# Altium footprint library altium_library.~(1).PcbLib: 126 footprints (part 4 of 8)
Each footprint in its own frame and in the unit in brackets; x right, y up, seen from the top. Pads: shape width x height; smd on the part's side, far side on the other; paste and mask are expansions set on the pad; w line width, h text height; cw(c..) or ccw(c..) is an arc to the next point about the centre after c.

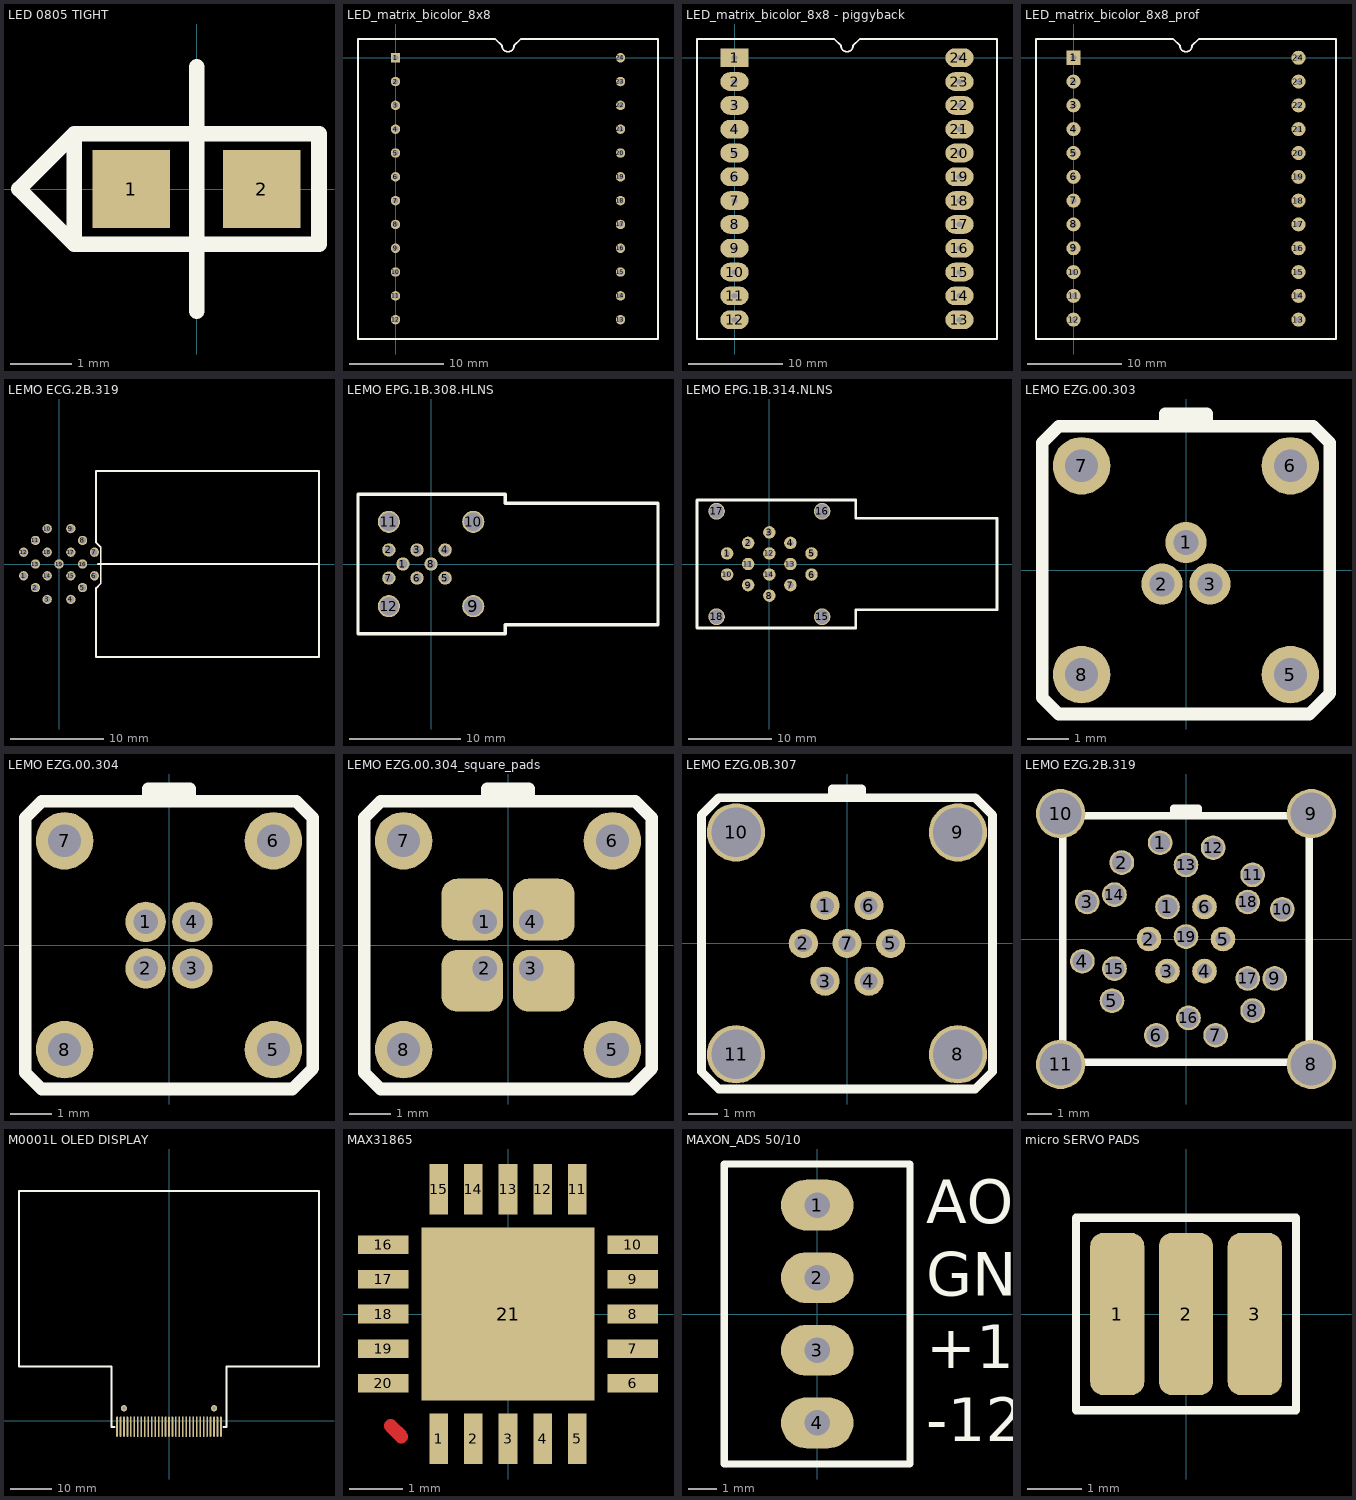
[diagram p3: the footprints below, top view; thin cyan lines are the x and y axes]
## LED 0805 TIGHT [mil]
pads (2):
  rect 50x50 smd: 1(-42,0) 2(42,0)
Top Overlay:
  lines w10: 0,-78.74 0,78.74 ; -114.17,0 -78.74,35.43 ; -114.17,0 -114.17,0 ; -114.17,0 -78.74,-35.43 ; -78.74,-35.43 -78.74,-26.74 -78.74,35.43 ; -78.74,-35.43 78.74,-35.43 78.74,35.43 -78.74,35.43

## LED_matrix_bicolor_8x8 [mm]
pads (24):
  rect 1x1 / inner rect 3x2 / far side rect 3x2 hole 0.6: 1(0,0)
  round 1 / inner oval 3x2 / far side oval 3x2 hole 0.6: 2(0,-2.54) 3(0,-5.08) 4(0,-7.62) 5(0,-10.16) 6(0,-12.7) 7(0,-15.24) 8(0,-17.78) 9(0,-20.32) 10(0,-22.86) 11(0,-25.4) 12(0,-27.94) 13(24,-27.94) 14(24,-25.4) 15(24,-22.86) 16(24,-20.32) 17(24,-17.78) 18(24,-15.24) 19(24,-12.7) 20(24,-10.16) 21(24,-7.62) 22(24,-5.08) 23(24,-2.54) 24(24,0)
Top Overlay:
  lines w0.2: -4,-30 -4,2 10.635,2 11.365,1.27 ccw(c12,1.27) 12.635,1.27 13.365,2 28,2 28,-30 -4,-30

## LED_matrix_bicolor_8x8 - piggyback [mm]
pads (24):
  rect 3x2 hole 0.6: 1(0,0)
  oval 3x2 hole 0.6: 2(0,-2.54) 3(0,-5.08) 4(0,-7.62) 5(0,-10.16) 6(0,-12.7) 7(0,-15.24) 8(0,-17.78) 9(0,-20.32) 10(0,-22.86) 11(0,-25.4) 12(0,-27.94) 13(24,-27.94) 14(24,-25.4) 15(24,-22.86) 16(24,-20.32) 17(24,-17.78) 18(24,-15.24) 19(24,-12.7) 20(24,-10.16) 21(24,-7.62) 22(24,-5.08) 23(24,-2.54) 24(24,0)
Top Overlay:
  lines w0.2: -4,-30 28,-30 28,2 13.365,2 12.635,1.27 cw(c12,1.27) 11.365,1.27 10.635,2 -4,2 -4,-30

## LED_matrix_bicolor_8x8_prof [mm] "made for proffesional pcb manuf."
height 8
pads (24):
  rect 1.5x1.5 hole 0.6: 1(0,0)
  round 1.5 hole 0.6: 2(0,-2.54) 3(0,-5.08) 4(0,-7.62) 5(0,-10.16) 6(0,-12.7) 7(0,-15.24) 8(0,-17.78) 9(0,-20.32) 10(0,-22.86) 11(0,-25.4) 12(0,-27.94) 13(24,-27.94) 14(24,-25.4) 15(24,-22.86) 16(24,-20.32) 17(24,-17.78) 18(24,-15.24) 19(24,-12.7) 20(24,-10.16) 21(24,-7.62) 22(24,-5.08) 23(24,-2.54) 24(24,0)
Top Overlay:
  lines w0.2: -4,-30 -4,2 10.635,2 11.365,1.27 ccw(c12,1.27) 12.635,1.27 13.365,2 28,2 28,-30 -4,-30

## LEMO ECG.2B.319 [mm]
pads (19):
  round 1 hole 0.7: 1(-3.81,-1.27) 2(-2.54,-2.54) 3(-1.27,-3.81) 4(1.27,-3.81) 5(2.54,-2.54) 6(3.81,-1.27) 7(3.81,1.27) 8(2.54,2.54) 9(1.27,3.81) 10(-1.27,3.81) 11(-2.54,2.54) 12(-3.81,1.27) 13(-2.54,0) 14(-1.27,-1.27) 15(1.27,-1.27) 16(2.54,0) 17(1.27,1.27) 18(-1.27,1.27) 19(0,0)
Top Overlay:
  lines w0.203: 4.2,0 28,0 ; 4.4,1.9 4,2.3 4,10 28,10 28,0 ; 4.4,1.9 4.4,1.9 ; 4.4,1.9 4.5,1.8 4.5,-2.1 4,-2.6 4,-10 28,-10 28,0

## LEMO EPG.1B.308.HLNS [mm]
height 14
pads (12):
  round 1.2 hole 0.8: 1(-2.54,0) 2(-3.81,1.27) 3(-1.27,1.27) 4(1.27,1.27) 5(1.27,-1.27) 6(-1.27,-1.27) 7(-3.81,-1.27) 8(0,0)
  round 2 / inner round 3 / far side round 3.6 hole 1.7: 9(3.81,-3.81) 10(3.81,3.81) 11(-3.81,3.81) 12(-3.81,-3.81)
Top Overlay:
  lines w0.305: -6.6,-6.3 -6.6,6.3 6.7,6.3 6.7,5.5 20.5,5.5 20.5,-5.5 6.7,-5.5 6.7,-6.3 -6.6,-6.3

## LEMO EPG.1B.314.NLNS [mm]
height 14.3
pads (18):
  round 1.5 hole 0.7: 1(-5.08,1.27) 2(-2.54,2.54) 3(0,3.81) 4(2.54,2.54) 5(5.08,1.27) 6(5.08,-1.27) 7(2.54,-2.54) 8(0,-3.81) 9(-2.54,-2.54) 10(-5.08,-1.27) 11(-2.54,0) 12(0,1.27) 13(2.54,0) 14(0,-1.27)
  round 2 / inner round 3 / far side round 4.1 hole 1.7: 15(6.35,-6.35) 16(6.35,6.35) 17(-6.35,6.35) 18(-6.35,-6.35)
Top Overlay:
  lines w0.305: -8.7,-7.7 -8.7,7.7 10.4,7.7 10.4,5.5 27.4,5.5 27.4,-5.5 10.4,-5.5 10.4,-7.7 -8.7,-7.7

## LEMO EZG.00.303 [mm]
height 15
pads (7):
  round 1 hole 0.6: 1(0,0.675) 2(-0.585,-0.337) 3(0.585,-0.337)
  round 1.4 / inner round 2 / far side round 2 hole 0.8: 5(2.54,-2.54) 6(2.54,2.54) 7(-2.54,2.54) 8(-2.54,-2.54)
Top Overlay:
  lines w0.305: -0.5,3.5 -0.5,3.8 0.5,3.8 0.5,3.5 ; 3.5,-3 3.5,3.1 3.1,3.5 -3.1,3.5 -3.5,3.1 -3.5,-3.1 -3.1,-3.5 3,-3.5 3.5,-3 ; 3.5,-3 3.5,-3

## LEMO EZG.00.304 [mm]
height 15
pads (8):
  round 0.982 hole 0.6: 1(-0.567,0.567) 2(-0.567,-0.567) 3(0.567,-0.567) 4(0.567,0.567)
  round 1.4 / inner round 2 / far side round 2 hole 0.8: 5(2.54,-2.54) 6(2.54,2.54) 7(-2.54,2.54) 8(-2.54,-2.54)
Top Overlay:
  lines w0.305: -0.5,3.5 -0.5,3.8 0.5,3.8 0.5,3.5 ; 3.5,-3 3,-3.5 -3.1,-3.5 -3.5,-3.1 -3.5,3.1 -3.1,3.5 3.1,3.5 3.5,3.1 3.5,-3 ; 3.5,-3 3.5,-3

## LEMO EZG.00.304_square_pads [mm]
height 15
pads (8):
  rrect50% 1.5x1.5 hole 0.6 copper offset -0.3,0.3: 1(-0.567,0.567)
  rrect50% 1.5x1.5 hole 0.6 copper offset -0.3,-0.3: 2(-0.567,-0.567)
  rrect50% 1.5x1.5 hole 0.6 copper offset 0.3,-0.3: 3(0.567,-0.567)
  rrect50% 1.5x1.5 hole 0.6 copper offset 0.3,0.3: 4(0.567,0.567)
  round 1.4 / inner round 2 / far side round 2 hole 0.8: 5(2.54,-2.54) 6(2.54,2.54) 7(-2.54,2.54) 8(-2.54,-2.54)
Top Overlay:
  lines w0.305: -0.5,3.5 -0.5,3.8 0.5,3.8 0.5,3.5 ; 3.5,-3 3,-3.5 -3.1,-3.5 -3.5,-3.1 -3.5,3.1 -3.1,3.5 3.1,3.5 3.5,3.1 3.5,-3 ; 3.5,-3 3.5,-3

## LEMO EZG.0B.307 [mm]
height 15
pads (11):
  round 1 hole 0.6: 1(-0.75,1.299) 2(-1.5,0) 3(-0.75,-1.299) 4(0.75,-1.299) 5(1.5,0) 6(0.75,1.299) 7(0,0)
  round 2 / inner round 3 / far side round 4.1 hole 1.7: 8(3.81,-3.81) 9(3.81,3.81) 10(-3.81,3.81) 11(-3.81,-3.81)
Top Overlay:
  lines w0.305: -0.5,5 -0.5,5.3 0.5,5.3 0.5,5 ; -5,-4.4 -4.4,-5 4.4,-5 5,-4.4 5,4.4 4.4,5 -4.4,5 -5,4.4 -5,-4.4

## LEMO EZG.2B.319 [mm]
height 22.5
pads (29):
  round 1 hole 0.8: 1(-1.05,3.899) 1(-0.75,1.299) 2(-2.6,3.1) 3(-4,1.5) 4(-4.2,-0.9) 5(-3,-2.5) 6(-1.2,-3.9) 7(1.2,-3.9) 8(2.7,-2.9) 9(3.6,-1.6) 10(3.9,1.2) 11(2.7,2.6) 12(1.1,3.7) 13(0,3) 14(-2.9,1.8) 15(-2.9,-1.2) 16(0.1,-3.2) 17(2.5,-1.6) 18(2.5,1.5) 19(0,0.1)
  round 1 hole 0.6: 2(-1.5,0) 3(-0.75,-1.299) 4(0.75,-1.299) 5(1.5,0) 6(0.75,1.299)
  round 2 / inner round 3 / far side round 4.1 hole 1.7: 8(5.08,-5.08) 9(5.08,5.08) 10(-5.08,5.08) 11(-5.08,-5.08)
Top Overlay:
  lines w0.305: -0.5,5 -0.5,5.3 0.5,5.3 0.5,5 ; -5,-4.4 -4.4,-5 4.4,-5 5,-4.4 5,4.4 4.4,5 -4.4,5 -5,4.4 -5,-4.4

## M0001L OLED DISPLAY [mm]
pads (33):
  oval 0.4x5 smd: 1(-12.675,-1.5) 2(-11.83,-1.5) 3(-10.985,-1.5) 4(-10.14,-1.5) 5(-9.295,-1.5) 6(-8.45,-1.5) 7(-7.605,-1.5) 8(-6.76,-1.5) 9(-5.915,-1.5) 10(-5.07,-1.5) 11(-4.225,-1.5) 12(-3.38,-1.5) 13(-2.535,-1.5) 14(-1.69,-1.5) 15(-0.845,-1.5) 16(0,-1.5) 17(0.845,-1.5) 18(1.69,-1.5) 19(2.535,-1.5) 20(3.38,-1.5) 21(4.225,-1.5) 22(5.07,-1.5) 23(5.915,-1.5) 24(6.76,-1.5) 25(7.605,-1.5) 26(8.45,-1.5) 27(9.295,-1.5) 28(10.14,-1.5) 29(10.985,-1.5) 30(11.83,-1.5) 31(12.675,-1.5)
  round 1.524 hole 0.762: 40(-11,3) 41(11,3)
Top Overlay:
  lines w0.508: -13.3,-1.6 -14,-1.6 -14,13.2 -36.6,13.2 -36.6,56 36.6,56 36.6,13.2 14,13.2 14,-1.6 13.3,-1.6

## MAX31865 [mm]
height 2
pads (21):
  rect 0.35x0.95 smd: 1(-1.3,-2.34) 2(-0.65,-2.34) 3(0,-2.34) 4(0.65,-2.34) 5(1.3,-2.34) 11(1.3,2.34) 12(0.65,2.34) 13(0,2.34) 14(-0.65,2.34) 15(-1.3,2.34)
  rect 0.95x0.35 smd: 6(2.34,-1.3) 7(2.34,-0.65) 8(2.34,0) 9(2.34,0.65) 10(2.34,1.3) 16(-2.34,1.3) 17(-2.34,0.65) 18(-2.34,0) 19(-2.34,-0.65) 20(-2.34,-1.3)
  rect 3.25x3.25 smd: 21(0,0)
Top Layer:
  lines w0.254: -2.2,-2.1 -2,-2.3 ; -2.2,-2.1 -2.2,-2.1 ; -2,-2.3 -2,-2.3

## MAXON_ADS 50/10 [mil] "conns to maxon motor driver"
pads (4):
  oval 100x70 hole 35.43: 1(0,150) 2(0,50) 3(0,-50) 4(0,-150)
Top Overlay:
  lines w10: -127.95,-206.69 -127.95,206.69 127.95,206.69 127.95,-206.69 -127.95,-206.69
  text "AO" at 150,125 h60
  text "GND" at 150,25 h60
  text "+12" at 150,-75 h60
  text "-12" at 150,-175 h60

## micro SERVO PADS [mm]
pads (3):
  rrect50% 1x3 smd mask+0.05: 1(-1.27,0) 2(0,0) 3(1.27,0)
Top Overlay:
  lines w0.152: -2.032,-1.778 -2.032,1.778 2.032,1.778 2.032,-1.778 -2.032,-1.778
  text "." at -2.159,1.397 h1.52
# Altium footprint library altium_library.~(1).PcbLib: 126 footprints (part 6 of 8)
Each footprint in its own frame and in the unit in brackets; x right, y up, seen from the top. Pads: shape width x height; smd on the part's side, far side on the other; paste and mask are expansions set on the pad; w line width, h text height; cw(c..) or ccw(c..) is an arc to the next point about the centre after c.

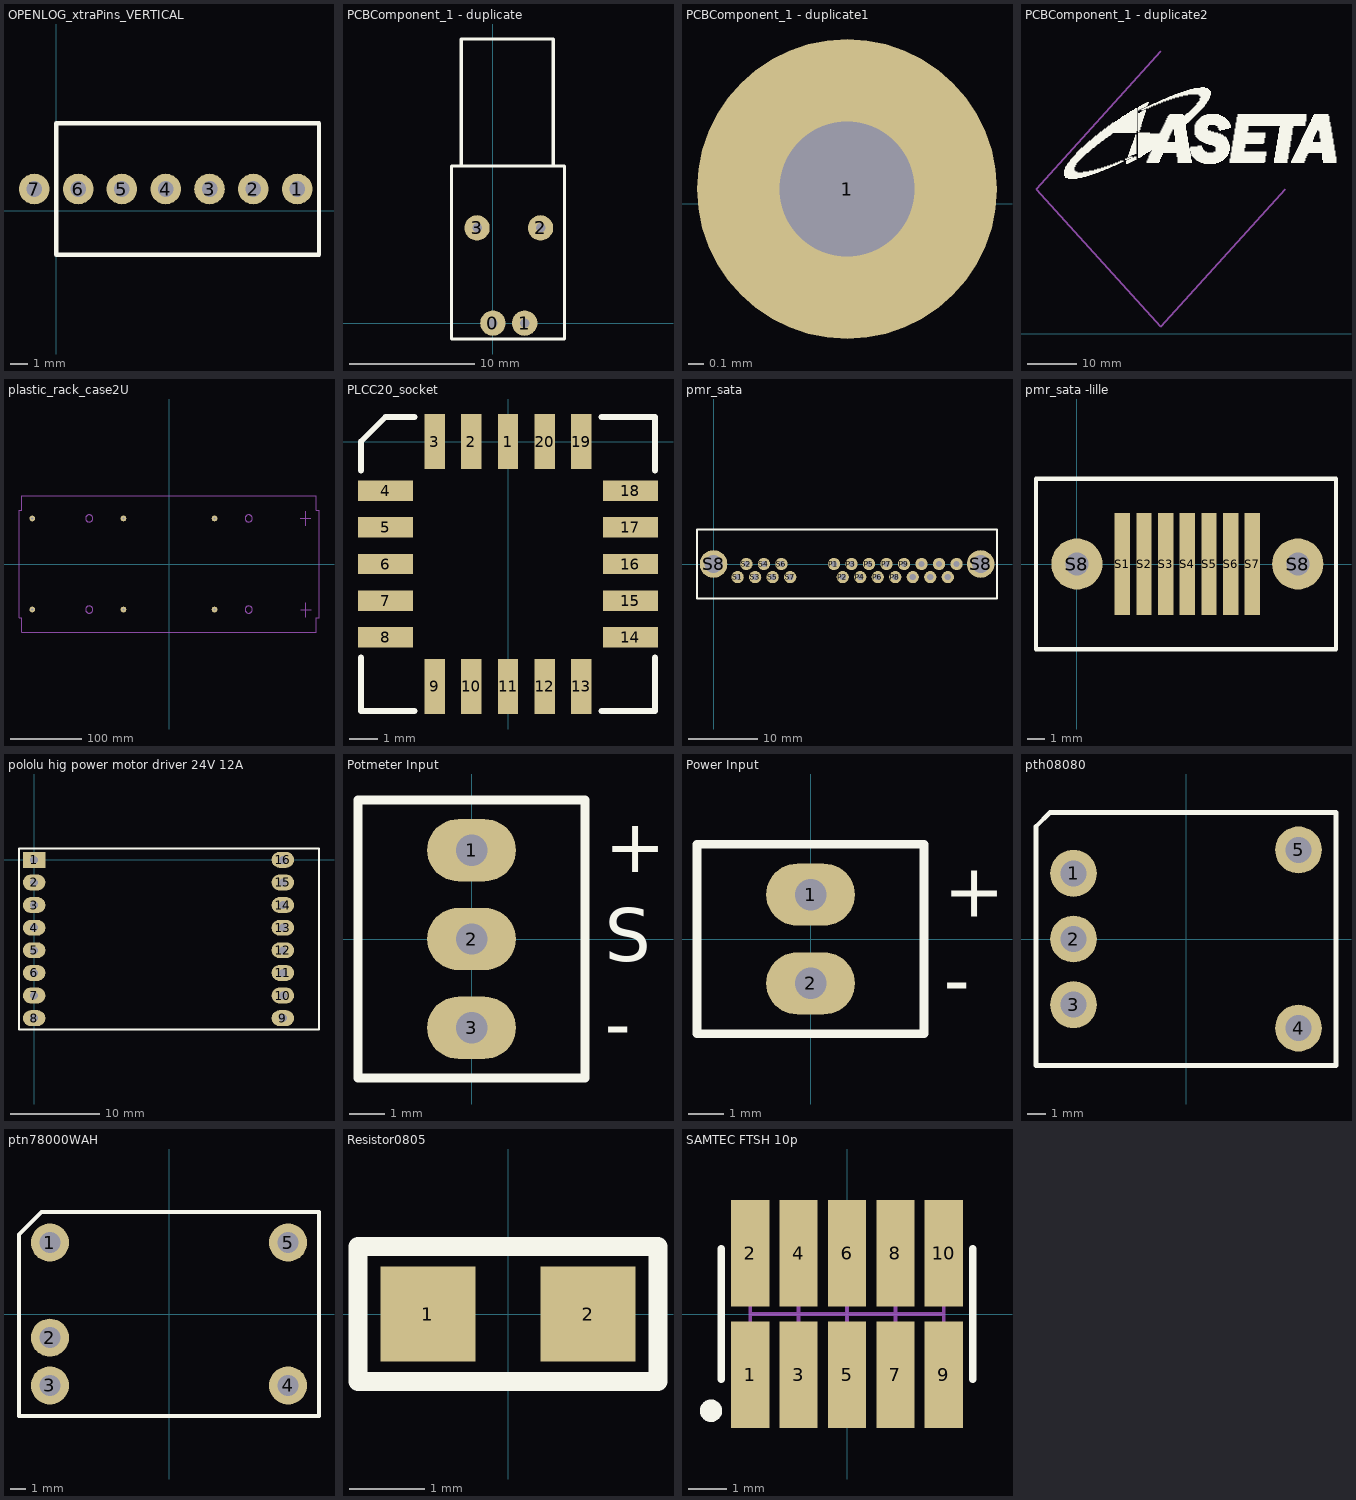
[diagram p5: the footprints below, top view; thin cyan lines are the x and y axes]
## OPENLOG_xtraPins_VERTICAL [mil] "Openlog vertical mounted + extra pin"
pads (7):
  round 70 hole 35.43: 1(550,50) 2(450,50) 3(350,50) 4(250,50) 5(150,50) 6(50,50) 7(-50,50)
Top Overlay:
  lines w10: 0,-100 600,-100 600,200 0,200 0,-100

## PCBComponent_1 [mil]

## PCBComponent_1 - duplicate [mil]
pads (4):
  round 80 hole 30: 0(0,0) 1(100,0) 2(150,300) 3(-50,300)
Top Overlay:
  lines w10: -100,495 -100,895 190,895 190,495 ; -130,-50 225,-50 225,495 -130,495 -130,-50

## PCBComponent_1 - duplicate1 [mm]
pads (1):
  round 2 hole 0.9: 1(-3.9,0.1)

## PCBComponent_1 - duplicate2 [mil]
Top Overlay:
  drawing of 6 lines, arcs and shapes, not listed
Mechanical 3:
  lines w10.44: 1527.56,2271.65 525.11,1165.89 1527.56,60.24 2530.01,1165.89

## plastic_rack_case2U [mm] "farnell 1526724"
pads (6):
  round 8 hole 3.2: 0(-63.5,-63.5) 1(-63.5,63.5) 2(-190.5,63.5) 3(-190.5,-63.5) 4(63.5,63.5) 5(63.5,-63.5)
Mechanical 3:
  lines w1: 183,63.5 197.5,63.5 ; 183.5,-63.5 198,-63.5 ; 190.5,-74 190.5,-54 ; 190.5,53.5 190.5,73.5
Mechanical 5:
  lines w0.254: -209,-75 -209,75 -205,75 -205,95 0,95 205,95 205,75 209,75 209,-75 205,-75 205,-95 -205,-95 -205,-75 -209,-75
Mechanical 6:
  circle w0.254: c-111.1,63.5 r5
  circle w0.254: c111.1,63.5 r5
  circle w0.254: c111.1,-63.5 r5
  circle w0.254: c-111.1,-63.5 r5

## PLCC20_socket [mm]
pads (20):
  rect 0.7x1.91 smd: 1(0,0) 2(-1.27,0) 3(-2.54,0) 9(-2.54,-8.48) 10(-1.27,-8.48) 11(0,-8.48) 12(1.27,-8.48) 13(2.54,-8.48) 19(2.54,0) 20(1.27,0)
  rect 1.91x0.7 smd: 4(-4.24,-1.7) 5(-4.24,-2.97) 6(-4.24,-4.24) 7(-4.24,-5.51) 8(-4.24,-6.78) 14(4.24,-6.78) 15(4.24,-5.51) 16(4.24,-4.24) 17(4.24,-2.97) 18(4.24,-1.7)
Top Overlay:
  lines w0.2: -5.095,-7.48 -5.095,-9.335 -3.24,-9.335 ; -5.095,-1 -5.095,0 -4.24,0.855 -3.24,0.855 ; 3.24,-9.335 5.095,-9.335 5.095,-7.48 ; 3.24,0.855 5.095,0.855 5.095,-1

## pmr_sata [mm]
pads (24):
  round 1.778 hole 0.9: P1(17.46,0) P2(18.73,-1.9) P3(20,0) P4(21.27,-1.9) P5(22.54,0) P6(23.81,-1.9) P7(25.08,0) P8(26.35,-1.9) P9(27.62,0) P10(28.89,-1.9) P11(30.16,0) P12(31.43,-1.9) P13(32.7,0) P14(33.97,-1.9) P15(35.24,0) S1(3.49,-1.9) S2(4.76,0) S3(6.03,-1.9) S4(7.3,0) S5(8.57,-1.9) S6(9.84,0) S7(11.11,-1.9)
  round 4 hole 2.6: S8(0,0) S8(38.74,0)
Top Overlay:
  lines w0.254: -2.4,-5 -2.4,5 41.1,5 41.1,-5 -2.4,-5

## pmr_sata -lille [mm]
pads (9):
  rect 0.9x6 smd: S1(2.67,0) S2(3.94,0) S3(5.21,0) S4(6.48,0) S5(7.75,0) S6(9.02,0) S7(10.29,0)
  round 3 hole 1.35: S8(0,0) S8(12.96,0)
Top Overlay:
  lines w0.254: -2.4,-5 -2.4,5 15.2,5 15.2,-5 -2.4,-5

## pololu hig power motor driver 24V 12A [mil]
pads (16):
  rect 100x70 hole 35: 1(0,0)
  oval 100x70 hole 35: 2(0,-100) 3(0,-200) 4(0,-300) 5(0,-400) 6(0,-500) 7(0,-600) 8(0,-700) 9(1100,-700) 10(1100,-600) 11(1100,-500) 12(1100,-400) 13(1100,-300) 14(1100,-200) 15(1100,-100) 16(1100,0)
Top Overlay:
  lines w10: 575,50 1259.84,50 1259.84,-750 -66.93,-750 -66.93,50 582.68,50

## Potmeter Input [mil] "Potmeter Input terminal cubli"
pads (3):
  oval 100x70 hole 35.43: 1(0,100) 2(0,0) 3(0,-100)
Top Overlay:
  lines w10: -127.95,-156.69 127.95,-156.69 127.95,156.69 -127.95,156.69 -127.95,-156.69
  text "-" at 150,-125 h60
  text "+" at 150,75 h60
  text "S" at 150,-25 h60

## Power Input [mil] "Power Input terminal cubli"
pads (2):
  oval 100x70 hole 35.43: 1(0,50) 2(0,-50)
Top Overlay:
  lines w10: -127.95,-106.69 127.95,-106.69 127.95,106.69 -127.95,106.69 -127.95,-106.69
  text "-" at 150,-75 h60
  text "+" at 150,25 h60

## pth08080 [mil] "DC dC converter"
pads (5):
  round 100 hole 55.12: 1(-240,140) 2(-240,0) 3(-240,-140) 4(240,-190) 5(240,190)
Top Overlay:
  lines w10: -320,-270 -320,240 -290,270 320,270 320,-270 -320,-270

## ptn78000WAH [mm] "DC dC converter"
pads (5):
  round 2.54 hole 1.4: 1(-7.94,4.76) 2(-7.94,-1.58) 3(-7.94,-4.76) 4(7.94,-4.76) 5(7.94,4.76)
Top Overlay:
  lines w0.254: -10,-6.8 -10,5.3 -8.5,6.8 10,6.8 10,-6.8 -10,-6.8

## Resistor0805 [mil]
pads (2):
  rect 50x50 smd: 1(-42,0) 2(42,0)
Top Overlay:
  lines w10: -78.74,-35.43 78.74,-35.43 78.74,35.43 -78.74,35.43 -78.74,-26.74 -78.74,-35.43

## SAMTEC FTSH 10p [mil] "samtec FTSH"
pads (10):
  rect 39.37x110 smd: 1(-100,-63) 2(-100,63) 3(-50,-63) 4(-50,63) 5(0,-63) 6(0,63) 7(50,-63) 8(50,63) 9(100,-63) 10(100,63)
Top Overlay:
  circle w12: c-140.57,-100 r5.57
  lines w8: -130,-67.5 -130,67.5 ; 130,-67.5 130,67.5
Mechanical 1:
  lines w3.94: -100,-25 -100,25 ; -100,0 100,0 ; -50,-25 -50,25 ; 0,-25 0,25 ; 50,-25 50,25 ; 100,-25 100,25
3D body: height 235.04, standoff 0, extent -124.99,-114.95 125,114.97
